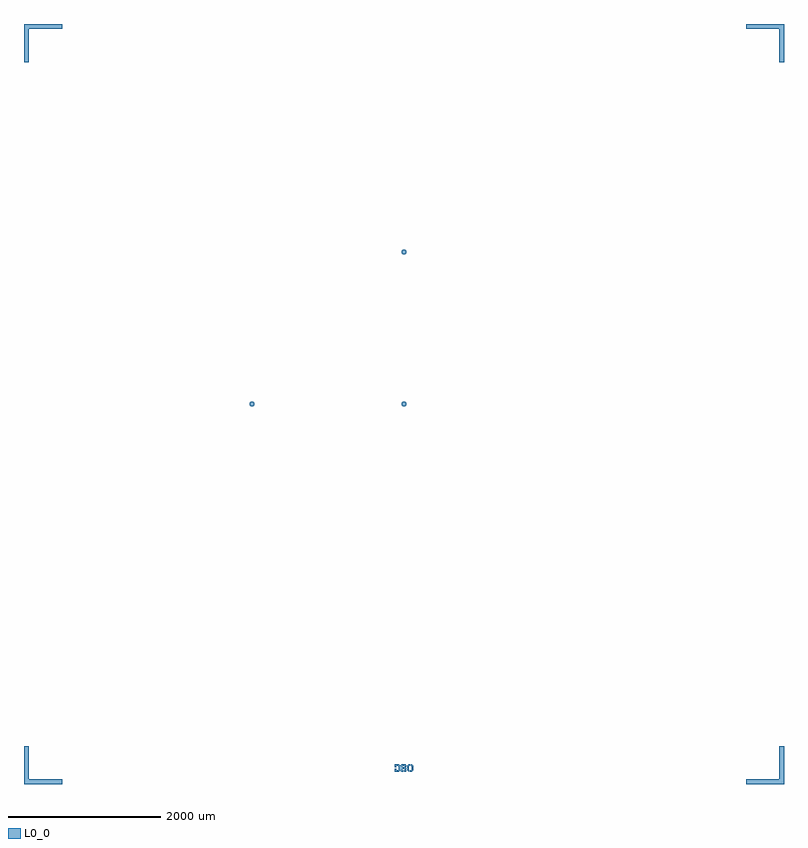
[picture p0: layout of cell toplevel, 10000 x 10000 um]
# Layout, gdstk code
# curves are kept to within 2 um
import gdstk
lib = gdstk.Library(unit=1e-6, precision=1e-09)
def P(c, l, *ps):  # polygons
    for p in ps: c.add(gdstk.Polygon(p, *l))
L0_0 = (0, 0)

circle = lib.new_cell('circle')
P(circle, L0_0, [(30,0),(27.716,11.481),(21.213,21.213),(11.481,27.716),(0,30),(-11.481,27.716),(-21.213,21.213),(-27.716,11.481),(-30,0),(-27.716,-11.481),(-21.213,-21.213),(-11.481,-27.716),(0,-30),(11.481,-27.716),(21.213,-21.213),(27.716,-11.481)])

circle001 = lib.new_cell('circle001')
P(circle001, L0_0, [(-1970,0),(-1972.284,11.481),(-1978.787,21.213),(-1988.519,27.716),(-2000,30),(-2011.481,27.716),(-2021.213,21.213),(-2027.716,11.481),(-2030,0),(-2027.716,-11.481),(-2021.213,-21.213),(-2011.481,-27.716),(-2000,-30),(-1988.519,-27.716),(-1978.787,-21.213),(-1972.284,-11.481)])

circle002 = lib.new_cell('circle002')
P(circle002, L0_0, [(30,2000),(27.716,2011.481),(21.213,2021.213),(11.481,2027.716),(0,2030),(-11.481,2027.716),(-21.213,2021.213),(-27.716,2011.481),(-30,2000),(-27.716,1988.519),(-21.213,1978.787),(-11.481,1972.284),(0,1970),(11.481,1972.284),(21.213,1978.787),(27.716,1988.519)])

text = lib.new_cell('text')
P(text, L0_0, [(10,0),(10,40),(30,40),(30,20),(50,20),(60,30),(60,70),(50,80),(30,80),(30,60),(10,60),(10,100),(60,100),(80,80),(80,20),(60,0)],
  [(160,70),(140,70),(140,80),(110,80),(110,60),(150,60),(160,50),(160,10),(150,0),(130,0),(130,20),(140,20),(140,40),(110,40),(110,20),(120,20),(120,0),(100,0),(90,10),(90,90),(100,100),(150,100),(160,90)],
  [(200,80),(190,70),(190,30),(200,20),(195,0),(190,0),(170,20),(170,80),(190,100),(213,100),(208,80),(200,80)],
  [(220,20),(230,30),(230,70),(220,80),(225,100),(230,100),(250,80),(250,20),(230,0),(207,0),(212,20),(220,20)])

die = lib.new_cell('die')
P(die, L0_0, [(5000,5000),(5000,4500),(4940,4500),(4940,4940),(4500,4940),(4500,5000)],
  [(-5000,5000),(-5000,4500),(-4940,4500),(-4940,4940),(-4500,4940),(-4500,5000)],
  [(5000,-5000),(5000,-4500),(4940,-4500),(4940,-4940),(4500,-4940),(4500,-5000)],
  [(-5000,-5000),(-5000,-4500),(-4940,-4500),(-4940,-4940),(-4500,-4940),(-4500,-5000)])
die.add(gdstk.Reference(text, (-130,-4840)))

toplevel = lib.new_cell('toplevel')
toplevel.add(gdstk.Reference(circle, (0,0)))
toplevel.add(gdstk.Reference(circle001, (0,0)))
toplevel.add(gdstk.Reference(circle002, (0,0)))
toplevel.add(gdstk.Reference(die, (0,0)))

lib.write_gds('toplevel.gds')
